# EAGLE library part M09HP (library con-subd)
SUB-D

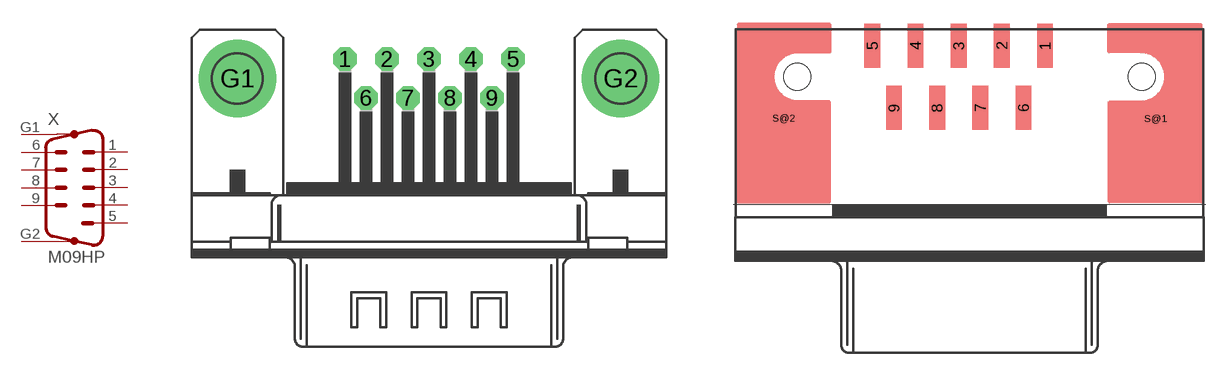
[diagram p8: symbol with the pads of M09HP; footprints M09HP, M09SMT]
Designator prefix X

## M09HP (OC_FARNELL: unknown; OC_NEWARK: unknown)  [M09HP]
1  1  pas
2  2  pas
3  3  pas
4  4  pas
5  5  pas
6  6  pas
7  7  pas
8  8  pas
9  9  pas
G1  G1  pas
G2  G2  pas

## M09HPSMT  [M09SMT]
1  1  pas
2  2  pas
3  3  pas
4  4  pas
5  5  pas
6  6  pas
7  7  pas
8  8  pas
9  9  pas
S@1  G1  pas
S@2  G2  pas

## Footprint M09HP (pad centres in mm)
SUB-D
drill 1.016 octagon: 1 -5.486,1.27; 2 -2.743,1.27; 3 0,1.27; 4 2.743,1.27; 5 5.486,1.27; 6 -4.115,-1.27; 7 -1.372,-1.27; 8 1.372,-1.27; 9 4.115,-1.27
drill 3.302 pad 5.08: G1 -12.522,0; G2 12.522,0

## Footprint M09SMT (pad centres in mm)
D-Sub Steckverbinder Abgewinkelte Messerleisten SMT, Einbauhöhe 3,6mm Source: ERNI-D-Sub-Conmnectors-d.pdf / www.erni.com
smd 1 x 2.8: 1 5.48,1.975; 2 2.74,1.975; 3 0,1.975; 4 -2.74,1.975; 5 -5.48,1.975; 6 4.11,-1.975; 7 1.37,-1.975; 8 -1.37,-1.975; 9 -4.11,-1.975
smd 1 x 1: S@1 12.485,-2.65; S@2 -11.115,-2.625
hole 1.7 at -10.24,0
hole 1.7 at 11.61,0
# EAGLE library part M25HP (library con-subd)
SUB-D

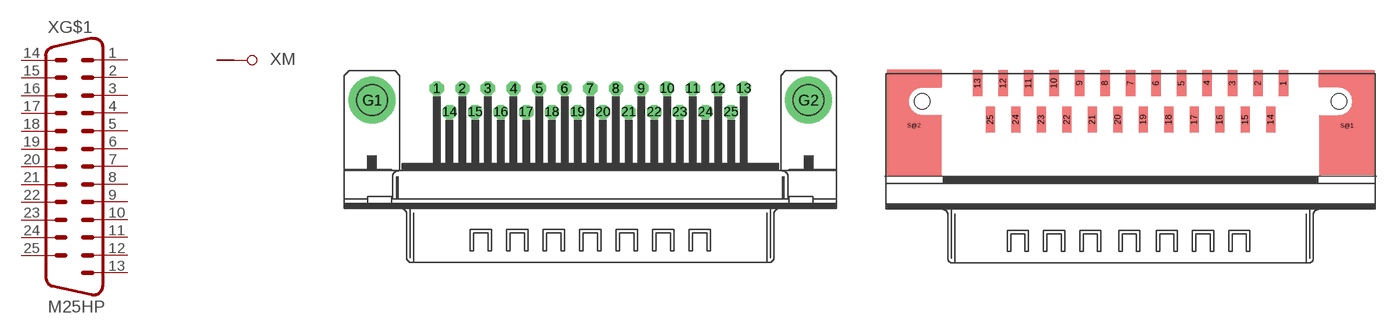
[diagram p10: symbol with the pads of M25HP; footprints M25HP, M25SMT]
Designator prefix X; gates G$1=M25 M=GND

## M25HP (OC_FARNELL: unknown; OC_NEWARK: unknown)  [M25HP]
1  G$1:1  pas
2  G$1:2  pas
3  G$1:3  pas
4  G$1:4  pas
5  G$1:5  pas
6  G$1:6  pas
7  G$1:7  pas
8  G$1:8  pas
9  G$1:9  pas
10  G$1:10  pas
11  G$1:11  pas
12  G$1:12  pas
13  G$1:13  pas
14  G$1:14  pas
15  G$1:15  pas
16  G$1:16  pas
17  G$1:17  pas
18  G$1:18  pas
19  G$1:19  pas
20  G$1:20  pas
21  G$1:21  pas
22  G$1:22  pas
23  G$1:23  pas
24  G$1:24  pas
25  G$1:25  pas
G1  M:G1  pas
G2  M:G2  pas

## M25HPSMT  [M25SMT]
1  G$1:1  pas
2  G$1:2  pas
3  G$1:3  pas
4  G$1:4  pas
5  G$1:5  pas
6  G$1:6  pas
7  G$1:7  pas
8  G$1:8  pas
9  G$1:9  pas
10  G$1:10  pas
11  G$1:11  pas
12  G$1:12  pas
13  G$1:13  pas
14  G$1:14  pas
15  G$1:15  pas
16  G$1:16  pas
17  G$1:17  pas
18  G$1:18  pas
19  G$1:19  pas
20  G$1:20  pas
21  G$1:21  pas
22  G$1:22  pas
23  G$1:23  pas
24  G$1:24  pas
25  G$1:25  pas
S@1  M:G1  pas
S@2  M:G2  pas

## Footprint M25HP (pad centres in mm)
SUB-D
drill 1.016 octagon: 1 -16.561,1.27; 2 -13.792,1.27; 3 -11.049,1.27; 4 -8.28,1.27; 5 -5.512,1.27; 6 -2.769,1.27; 7 0,1.27; 8 2.769,1.27; 9 5.512,1.27; 10 8.28,1.27; 11 11.049,1.27; 12 13.792,1.27; 13 16.561,1.27; 14 -15.189,-1.27; 15 -12.421,-1.27; 16 -9.652,-1.27; 17 -6.909,-1.27; 18 -4.14,-1.27; 19 -1.372,-1.27; 20 1.372,-1.27; 21 4.14,-1.27; 22 6.909,-1.27; 23 9.652,-1.27; 24 12.421,-1.27; 25 15.189,-1.27
drill 3.302 pad 5.08: G1 -23.52,0; G2 23.52,0

## Footprint M25SMT (pad centres in mm)
D-Sub Steckverbinder Abgewinkelte Messerleisten SMT, Einbauhöhe 3,6mm Source: ERNI-D-Sub-Conmnectors-d.pdf / www.erni.com
smd 1 x 2.8: 1 16.56,1.975; 2 13.8,1.975; 3 11.04,1.975; 4 8.28,1.975; 5 5.52,1.975; 6 2.76,1.975; 7 0,1.975; 8 -2.76,1.975; 9 -5.52,1.975; 10 -8.28,1.975; 11 -11.04,1.975; 12 -13.8,1.975; 13 -16.56,1.975; 14 15.18,-1.975; 15 12.42,-1.975; 16 9.66,-1.975; 17 6.9,-1.975; 18 4.14,-1.975; 19 1.38,-1.975; 20 -1.38,-1.975; 21 -4.14,-1.975; 22 -6.9,-1.975; 23 -9.66,-1.975; 24 -12.42,-1.975; 25 -15.18,-1.975
smd 1 x 1: S@1 23.445,-2.65; S@2 -23.445,-2.625
hole 1.7 at -22.57,0
hole 1.7 at 22.57,0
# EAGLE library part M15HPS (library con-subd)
SUB-D

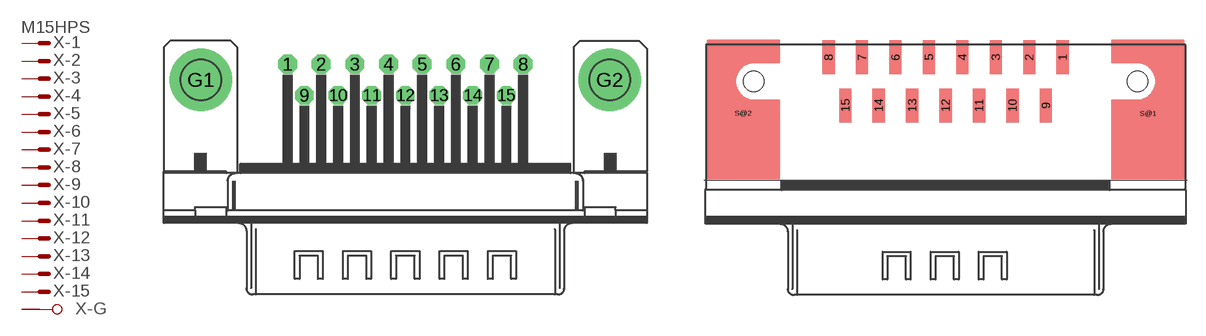
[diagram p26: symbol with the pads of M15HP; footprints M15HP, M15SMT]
Designator prefix X; gates -2=M -3=M -4=M -5=M -6=M -7=M -8=M -9=M -10=M -11=M -12=M -13=M -14=M -15=M -G=GND -1=MV

## M15HPS (OC_FARNELL: unknown; OC_NEWARK: unknown)  [M15HP]
1  -1:M  pas
2  -2:M  pas
3  -3:M  pas
4  -4:M  pas
5  -5:M  pas
6  -6:M  pas
7  -7:M  pas
8  -8:M  pas
9  -9:M  pas
10  -10:M  pas
11  -11:M  pas
12  -12:M  pas
13  -13:M  pas
14  -14:M  pas
15  -15:M  pas
G1  -G:G1  pas
G2  -G:G2  pas

## M15HPSSMT  [M15SMT]
1  -1:M  pas
2  -2:M  pas
3  -3:M  pas
4  -4:M  pas
5  -5:M  pas
6  -6:M  pas
7  -7:M  pas
8  -8:M  pas
9  -9:M  pas
10  -10:M  pas
11  -11:M  pas
12  -12:M  pas
13  -13:M  pas
14  -14:M  pas
15  -15:M  pas
S@1  -G:G1  pas
S@2  -G:G2  pas

## Footprint M15HP (pad centres in mm)
SUB-D
drill 1.016 octagon: 1 -9.601,1.27; 2 -6.858,1.27; 3 -4.115,1.27; 4 -1.372,1.27; 5 1.372,1.27; 6 4.115,1.27; 7 6.858,1.27; 8 9.601,1.27; 9 -8.23,-1.27; 10 -5.486,-1.27; 11 -2.743,-1.27; 12 0,-1.27; 13 2.743,-1.27; 14 5.486,-1.27; 15 8.23,-1.27
drill 3.302 pad 5.08: G1 -16.662,0; G2 16.662,0

## Footprint M15SMT (pad centres in mm)
D-Sub Steckverbinder Abgewinkelte Messerleisten SMT, Einbauhöhe 3,6mm Source: ERNI-D-Sub-Conmnectors-d.pdf / www.erni.com
smd 1 x 2.8: 1 9.59,1.975; 2 6.85,1.975; 3 4.11,1.975; 4 1.37,1.975; 5 -1.37,1.975; 6 -4.11,1.975; 7 -6.85,1.975; 8 -9.59,1.975; 9 8.22,-1.975; 10 5.48,-1.975; 11 2.74,-1.975; 12 0,-1.975; 13 -2.74,-1.975; 14 -5.48,-1.975; 15 -8.22,-1.975
smd 1 x 1: S@1 16.595,-2.65; S@2 -16.595,-2.625
hole 1.7 at -15.72,0
hole 1.7 at 15.72,0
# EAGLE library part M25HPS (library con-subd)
SUB-D

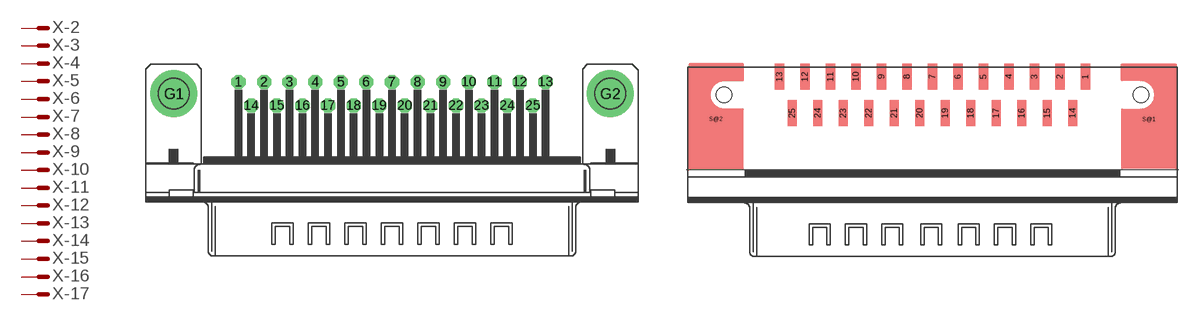
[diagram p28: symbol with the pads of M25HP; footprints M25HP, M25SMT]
Designator prefix X; gates -2=M -3=M -4=M -5=M -6=M -7=M -8=M -9=M -10=M -11=M -12=M -13=M -14=M -15=M -16=M -17=M -18=M -19=M -20=M -21=M -22=M -23=M -24=M -25=M -G=GND -1=MV

## M25HPS (OC_FARNELL: unknown; OC_NEWARK: unknown)  [M25HP]
1  -1:M  pas
2  -2:M  pas
3  -3:M  pas
4  -4:M  pas
5  -5:M  pas
6  -6:M  pas
7  -7:M  pas
8  -8:M  pas
9  -9:M  pas
10  -10:M  pas
11  -11:M  pas
12  -12:M  pas
13  -13:M  pas
14  -14:M  pas
15  -15:M  pas
16  -16:M  pas
17  -17:M  pas
18  -18:M  pas
19  -19:M  pas
20  -20:M  pas
21  -21:M  pas
22  -22:M  pas
23  -23:M  pas
24  -24:M  pas
25  -25:M  pas
G1  -G:G1  pas
G2  -G:G2  pas

## M25HPSSMT  [M25SMT]
1  -1:M  pas
2  -2:M  pas
3  -3:M  pas
4  -4:M  pas
5  -5:M  pas
6  -6:M  pas
7  -7:M  pas
8  -8:M  pas
9  -9:M  pas
10  -10:M  pas
11  -11:M  pas
12  -12:M  pas
13  -13:M  pas
14  -14:M  pas
15  -15:M  pas
16  -16:M  pas
17  -17:M  pas
18  -18:M  pas
19  -19:M  pas
20  -20:M  pas
21  -21:M  pas
22  -22:M  pas
23  -23:M  pas
24  -24:M  pas
25  -25:M  pas
S@1  -G:G1  pas
S@2  -G:G2  pas

## Footprint M25HP (pad centres in mm)
SUB-D
drill 1.016 octagon: 1 -16.561,1.27; 2 -13.792,1.27; 3 -11.049,1.27; 4 -8.28,1.27; 5 -5.512,1.27; 6 -2.769,1.27; 7 0,1.27; 8 2.769,1.27; 9 5.512,1.27; 10 8.28,1.27; 11 11.049,1.27; 12 13.792,1.27; 13 16.561,1.27; 14 -15.189,-1.27; 15 -12.421,-1.27; 16 -9.652,-1.27; 17 -6.909,-1.27; 18 -4.14,-1.27; 19 -1.372,-1.27; 20 1.372,-1.27; 21 4.14,-1.27; 22 6.909,-1.27; 23 9.652,-1.27; 24 12.421,-1.27; 25 15.189,-1.27
drill 3.302 pad 5.08: G1 -23.52,0; G2 23.52,0

## Footprint M25SMT (pad centres in mm)
D-Sub Steckverbinder Abgewinkelte Messerleisten SMT, Einbauhöhe 3,6mm Source: ERNI-D-Sub-Conmnectors-d.pdf / www.erni.com
smd 1 x 2.8: 1 16.56,1.975; 2 13.8,1.975; 3 11.04,1.975; 4 8.28,1.975; 5 5.52,1.975; 6 2.76,1.975; 7 0,1.975; 8 -2.76,1.975; 9 -5.52,1.975; 10 -8.28,1.975; 11 -11.04,1.975; 12 -13.8,1.975; 13 -16.56,1.975; 14 15.18,-1.975; 15 12.42,-1.975; 16 9.66,-1.975; 17 6.9,-1.975; 18 4.14,-1.975; 19 1.38,-1.975; 20 -1.38,-1.975; 21 -4.14,-1.975; 22 -6.9,-1.975; 23 -9.66,-1.975; 24 -12.42,-1.975; 25 -15.18,-1.975
smd 1 x 1: S@1 23.445,-2.65; S@2 -23.445,-2.625
hole 1.7 at -22.57,0
hole 1.7 at 22.57,0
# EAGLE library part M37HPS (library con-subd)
SUB-D

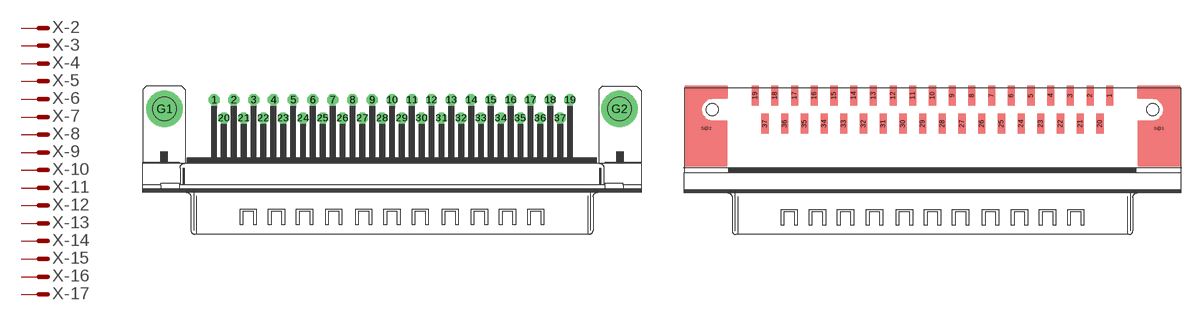
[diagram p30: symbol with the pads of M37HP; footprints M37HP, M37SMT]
Designator prefix X; gates -2=M -3=M -4=M -5=M -6=M -7=M -8=M -9=M -10=M -11=M -12=M -13=M -14=M -15=M -16=M -17=M -18=M -19=M -20=M -21=M -22=M -23=M -24=M -25=M -26=M -27=M -28=M -29=M -30=M -31=M -32=M -33=M -34=M -35=M -36=M -37=M -G=GND -1=MV

## M37HPS (OC_FARNELL: unknown; OC_NEWARK: unknown)  [M37HP]
1  -1:M  pas
2  -2:M  pas
3  -3:M  pas
4  -4:M  pas
5  -5:M  pas
6  -6:M  pas
7  -7:M  pas
8  -8:M  pas
9  -9:M  pas
10  -10:M  pas
11  -11:M  pas
12  -12:M  pas
13  -13:M  pas
14  -14:M  pas
15  -15:M  pas
16  -16:M  pas
17  -17:M  pas
18  -18:M  pas
19  -19:M  pas
20  -20:M  pas
21  -21:M  pas
22  -22:M  pas
23  -23:M  pas
24  -24:M  pas
25  -25:M  pas
26  -26:M  pas
27  -27:M  pas
28  -28:M  pas
29  -29:M  pas
30  -30:M  pas
31  -31:M  pas
32  -32:M  pas
33  -33:M  pas
34  -34:M  pas
35  -35:M  pas
36  -36:M  pas
37  -37:M  pas
G1  -G:G1  pas
G2  -G:G2  pas

## M37HPSSMT  [M37SMT]
1  -1:M  pas
2  -2:M  pas
3  -3:M  pas
4  -4:M  pas
5  -5:M  pas
6  -6:M  pas
7  -7:M  pas
8  -8:M  pas
9  -9:M  pas
10  -10:M  pas
11  -11:M  pas
12  -12:M  pas
13  -13:M  pas
14  -14:M  pas
15  -15:M  pas
16  -16:M  pas
17  -17:M  pas
18  -18:M  pas
19  -19:M  pas
20  -20:M  pas
21  -21:M  pas
22  -22:M  pas
23  -23:M  pas
24  -24:M  pas
25  -25:M  pas
26  -26:M  pas
27  -27:M  pas
28  -28:M  pas
29  -29:M  pas
30  -30:M  pas
31  -31:M  pas
32  -32:M  pas
33  -33:M  pas
34  -34:M  pas
35  -35:M  pas
36  -36:M  pas
37  -37:M  pas
S@1  -G:G1  pas
S@2  -G:G2  pas

## Footprint M37HP (pad centres in mm)
SUB-D
drill 1.016 octagon: 1 -24.841,1.27; 2 -22.098,1.27; 3 -19.329,1.27; 4 -16.561,1.27; 5 -13.818,1.27; 6 -11.049,1.27; 7 -8.28,1.27; 8 -5.512,1.27; 9 -2.769,1.27; 10 0,1.27; 11 2.769,1.27; 12 5.512,1.27; 13 8.28,1.27; 14 11.049,1.27; 15 13.792,1.27; 16 16.561,1.27; 17 19.329,1.27; 18 22.073,1.27; 19 24.841,1.27; 20 -23.47,-1.27; 21 -20.701,-1.27; 22 -17.958,-1.27; 23 -15.189,-1.27; 24 -12.421,-1.27; 25 -9.652,-1.27; 26 -6.909,-1.27; 27 -4.14,-1.27; 28 -1.372,-1.27; 29 1.372,-1.27; 30 4.14,-1.27; 31 6.909,-1.27; 32 9.652,-1.27; 33 12.421,-1.27; 34 15.189,-1.27; 35 17.932,-1.27; 36 20.701,-1.27; 37 23.47,-1.27
drill 3.302 pad 5.08: G1 -31.75,0; G2 31.75,0

## Footprint M37SMT (pad centres in mm)
D-Sub Steckverbinder Abgewinkelte Messerleisten SMT, Einbauhöhe 3,6mm Source: ERNI-D-Sub-Conmnectors-d.pdf / www.erni.com
smd 1 x 2.8: 1 24.84,1.975; 2 22.08,1.975; 3 19.32,1.975; 4 16.56,1.975; 5 13.8,1.975; 6 11.04,1.975; 7 8.28,1.975; 8 5.52,1.975; 9 2.76,1.975; 10 0,1.975; 11 -2.76,1.975; 12 -5.52,1.975; 13 -8.28,1.975; 14 -11.04,1.975; 15 -13.8,1.975; 16 -16.56,1.975; 17 -19.32,1.975; 18 -22.08,1.975; 19 -24.84,1.975; 20 23.46,-1.975; 21 20.7,-1.975; 22 17.94,-1.975; 23 15.18,-1.975; 24 12.42,-1.975; 25 9.66,-1.975; 26 6.9,-1.975; 27 4.14,-1.975; 28 1.38,-1.975; 29 -1.38,-1.975; 30 -4.14,-1.975; 31 -6.9,-1.975; 32 -9.66,-1.975; 33 -12.42,-1.975; 34 -15.18,-1.975; 35 -17.94,-1.975; 36 -20.7,-1.975; 37 -23.46,-1.975
smd 1 x 1: S@1 31.725,-2.65; S@2 -31.725,-2.625
hole 1.7 at -30.85,0
hole 1.7 at 30.85,0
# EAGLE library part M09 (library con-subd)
SUB-D

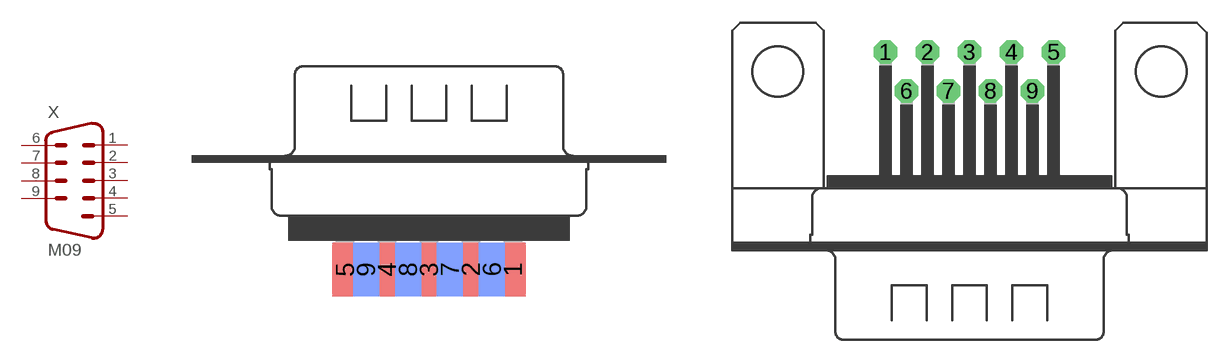
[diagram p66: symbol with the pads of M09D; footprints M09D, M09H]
Designator prefix X

## M09D (OC_FARNELL: unknown; OC_NEWARK: unknown)  [M09D]
1  1  pas
2  2  pas
3  3  pas
4  4  pas
5  5  pas
6  6  pas
7  7  pas
8  8  pas
9  9  pas

## M09H (OC_FARNELL: unknown; OC_NEWARK: unknown)  [M09H]
Pads as for M09D

## M09HP (OC_FARNELL: unknown; OC_NEWARK: unknown)  [M09HP]
Pads as for M09D

## M09V (OC_FARNELL: unknown; OC_NEWARK: unknown)  [M09V]
Pads as for M09D

## M09VP (OC_FARNELL: unknown; OC_NEWARK: unknown)  [M09VP]
Pads as for M09D

## M09VB (OC_FARNELL: unknown; OC_NEWARK: unknown)  [M09VB]
Pads as for M09D

## M09-182 (OC_FARNELL: unknown; OC_NEWARK: unknown)  [182-009-MALE]
Pads as for M09D

## M09SMT  [M09SMT]
Pads as for M09D

## Footprint M09D (pad centres in mm)
SUB-D
smd 1.7 x 3.5: 1 5.486,-6.045; 2 2.743,-6.045; 3 0,-6.045; 4 -2.743,-6.045; 5 -5.486,-6.045
smd 1.7 x 3.5 bottom: 6 4.115,-6.045; 7 1.372,-6.045; 8 -1.372,-6.045; 9 -4.115,-6.045

## Footprint M09H (pad centres in mm)
SUB-D
drill 1.016 octagon: 1 -5.486,1.27; 2 -2.743,1.27; 3 0,1.27; 4 2.743,1.27; 5 5.486,1.27; 6 -4.115,-1.27; 7 -1.372,-1.27; 8 1.372,-1.27; 9 4.115,-1.27
hole 3.302 at 12.522,0
hole 3.302 at -12.522,0

## Footprint M09HP (pad centres in mm)
SUB-D
drill 1.016 octagon: 1 -5.486,1.27; 2 -2.743,1.27; 3 0,1.27; 4 2.743,1.27; 5 5.486,1.27; 6 -4.115,-1.27; 7 -1.372,-1.27; 8 1.372,-1.27; 9 4.115,-1.27
drill 3.302 pad 5.08: G1 -12.522,0; G2 12.522,0

## Footprint M09V (pad centres in mm)
SUB-D
drill 1.016 octagon: 1 -5.486,1.422; 2 -2.743,1.422; 3 0,1.422; 4 2.743,1.422; 5 5.486,1.422; 6 -4.115,-1.422; 7 -1.372,-1.422; 8 1.372,-1.422; 9 4.115,-1.422
hole 3.302 at -12.522,0
hole 3.302 at 12.522,0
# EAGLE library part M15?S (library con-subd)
SUB-D

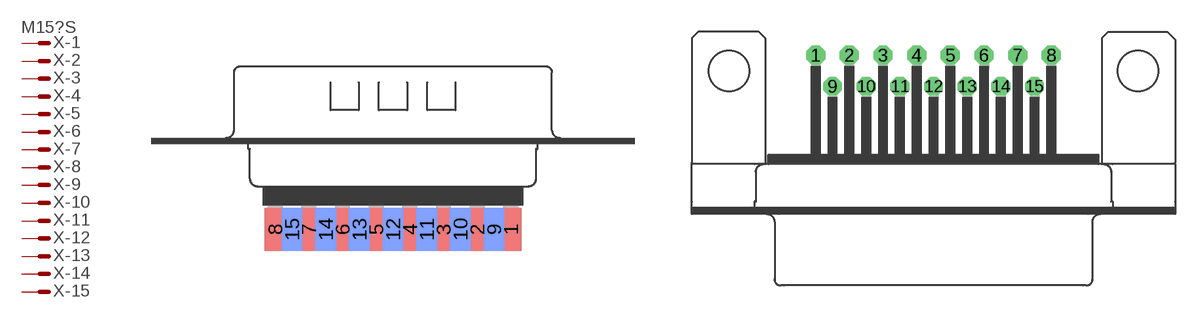
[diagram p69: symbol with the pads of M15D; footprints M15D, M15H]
Designator prefix X; gates -1=MV -2=M -3=M -4=M -5=M -6=M -7=M -8=M -9=M -10=M -11=M -12=M -13=M -14=M -15=M

## M15DS (OC_FARNELL: unknown; OC_NEWARK: unknown)  [M15D]
1  -1:M  pas
2  -2:M  pas
3  -3:M  pas
4  -4:M  pas
5  -5:M  pas
6  -6:M  pas
7  -7:M  pas
8  -8:M  pas
9  -9:M  pas
10  -10:M  pas
11  -11:M  pas
12  -12:M  pas
13  -13:M  pas
14  -14:M  pas
15  -15:M  pas

## M15HS (OC_FARNELL: unknown; OC_NEWARK: unknown)  [M15H]
Pads as for M15D

## M15HPS (OC_FARNELL: unknown; OC_NEWARK: unknown)  [M15HP]
Pads as for M15D

## M15VS (OC_FARNELL: unknown; OC_NEWARK: unknown)  [M15V]
Pads as for M15D

## M15VPS (OC_FARNELL: unknown; OC_NEWARK: unknown)  [M15VP]
Pads as for M15D

## M15VBS (OC_FARNELL: unknown; OC_NEWARK: unknown)  [M15VB]
Pads as for M15D

## M15.590S (OC_FARNELL: unknown; OC_NEWARK: unknown)  [177-015-MALE]
Pads as for M15D

## M15-182S (OC_FARNELL: unknown; OC_NEWARK: unknown)  [182-015-MALE]
Pads as for M15D

## M15SMTS  [M15SMT]
Pads as for M15D

## Footprint M15D (pad centres in mm)
SUB-D
smd 1.7 x 3.5: 1 9.601,-6.045; 2 6.858,-6.045; 3 4.115,-6.045; 4 1.372,-6.045; 5 -1.372,-6.045; 6 -4.115,-6.045; 7 -6.858,-6.045; 8 -9.601,-6.045
smd 1.7 x 3.5 bottom: 9 8.23,-6.045; 10 5.486,-6.045; 11 2.743,-6.045; 12 0,-6.045; 13 -2.743,-6.045; 14 -5.486,-6.045; 15 -8.23,-6.045

## Footprint M15H (pad centres in mm)
SUB-D
drill 1.016 octagon: 1 -9.601,1.27; 2 -6.858,1.27; 3 -4.115,1.27; 4 -1.372,1.27; 5 1.372,1.27; 6 4.115,1.27; 7 6.858,1.27; 8 9.601,1.27; 9 -8.23,-1.27; 10 -5.486,-1.27; 11 -2.743,-1.27; 12 0,-1.27; 13 2.743,-1.27; 14 5.486,-1.27; 15 8.23,-1.27
hole 3.302 at 16.662,0
hole 3.302 at -16.662,0

## Footprint M15HP (pad centres in mm)
SUB-D
drill 1.016 octagon: 1 -9.601,1.27; 2 -6.858,1.27; 3 -4.115,1.27; 4 -1.372,1.27; 5 1.372,1.27; 6 4.115,1.27; 7 6.858,1.27; 8 9.601,1.27; 9 -8.23,-1.27; 10 -5.486,-1.27; 11 -2.743,-1.27; 12 0,-1.27; 13 2.743,-1.27; 14 5.486,-1.27; 15 8.23,-1.27
drill 3.302 pad 5.08: G1 -16.662,0; G2 16.662,0

## Footprint M15V (pad centres in mm)
SUB-D
drill 1.016 octagon: 1 -9.601,1.422; 2 -6.858,1.422; 3 -4.115,1.422; 4 -1.372,1.422; 5 1.372,1.422; 6 4.115,1.422; 7 6.858,1.422; 8 9.601,1.422; 9 -8.23,-1.422; 10 -5.486,-1.422; 11 -2.743,-1.422; 12 0,-1.422; 13 2.743,-1.422; 14 5.486,-1.422; 15 8.23,-1.422
hole 3.302 at 16.662,0
hole 3.302 at -16.662,0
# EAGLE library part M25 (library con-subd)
SUB-D

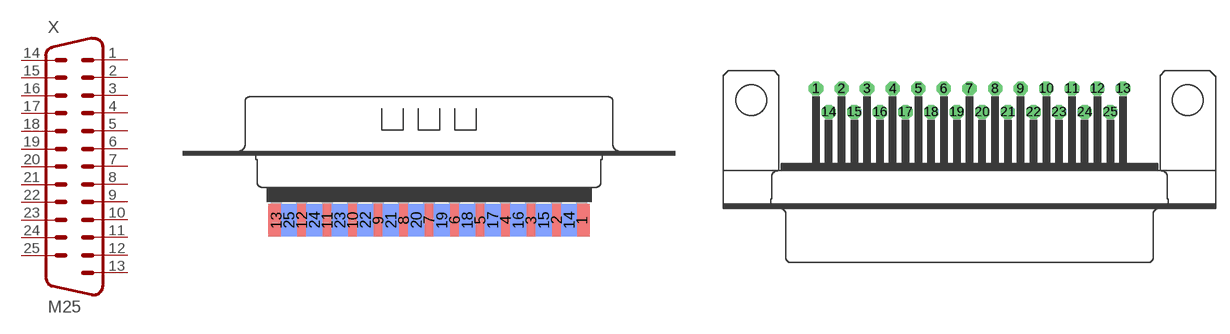
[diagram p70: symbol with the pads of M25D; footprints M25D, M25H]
Designator prefix X

## M25D (OC_FARNELL: unknown; OC_NEWARK: unknown)  [M25D]
1  1  pas
2  2  pas
3  3  pas
4  4  pas
5  5  pas
6  6  pas
7  7  pas
8  8  pas
9  9  pas
10  10  pas
11  11  pas
12  12  pas
13  13  pas
14  14  pas
15  15  pas
16  16  pas
17  17  pas
18  18  pas
19  19  pas
20  20  pas
21  21  pas
22  22  pas
23  23  pas
24  24  pas
25  25  pas

## M25H (OC_FARNELL: unknown; OC_NEWARK: unknown)  [M25H]
Pads as for M25D

## M25HP (OC_FARNELL: unknown; OC_NEWARK: unknown)  [M25HP]
Pads as for M25D

## M25V (OC_FARNELL: unknown; OC_NEWARK: unknown)  [M25V]
Pads as for M25D

## M25VP (OC_FARNELL: unknown; OC_NEWARK: unknown)  [M25VP]
Pads as for M25D

## M25VB (OC_FARNELL: unknown; OC_NEWARK: unknown)  [M25VB]
Pads as for M25D

## M25-182 (OC_FARNELL: unknown; OC_NEWARK: unknown)  [182-025-MALE]
Pads as for M25D

## M25SMT  [M25SMT]
Pads as for M25D

## Footprint M25D (pad centres in mm)
SUB-D
smd 1.7 x 3.5: 1 16.459,-6.045; 2 13.716,-6.045; 3 10.973,-6.045; 4 8.23,-6.045; 5 5.486,-6.045; 6 2.743,-6.045; 7 0,-6.045; 8 -2.743,-6.045; 9 -5.486,-6.045; 10 -8.23,-6.045; 11 -10.973,-6.045; 12 -13.716,-6.045; 13 -16.459,-6.045
smd 1.7 x 3.5 bottom: 14 15.088,-6.045; 15 12.344,-6.045; 16 9.601,-6.045; 17 6.858,-6.045; 18 4.115,-6.045; 19 1.372,-6.045; 20 -1.372,-6.045; 21 -4.115,-6.045; 22 -6.858,-6.045; 23 -9.601,-6.045; 24 -12.344,-6.045; 25 -15.088,-6.045

## Footprint M25H (pad centres in mm)
SUB-D
drill 1.016 octagon: 1 -16.561,1.27; 2 -13.792,1.27; 3 -11.049,1.27; 4 -8.28,1.27; 5 -5.512,1.27; 6 -2.769,1.27; 7 0,1.27; 8 2.769,1.27; 9 5.512,1.27; 10 8.28,1.27; 11 11.049,1.27; 12 13.792,1.27; 13 16.561,1.27; 14 -15.189,-1.27; 15 -12.421,-1.27; 16 -9.652,-1.27; 17 -6.909,-1.27; 18 -4.14,-1.27; 19 -1.372,-1.27; 20 1.372,-1.27; 21 4.14,-1.27; 22 6.909,-1.27; 23 9.652,-1.27; 24 12.421,-1.27; 25 15.189,-1.27
hole 3.302 at 23.52,0
hole 3.302 at -23.52,0

## Footprint M25HP (pad centres in mm)
SUB-D
drill 1.016 octagon: 1 -16.561,1.27; 2 -13.792,1.27; 3 -11.049,1.27; 4 -8.28,1.27; 5 -5.512,1.27; 6 -2.769,1.27; 7 0,1.27; 8 2.769,1.27; 9 5.512,1.27; 10 8.28,1.27; 11 11.049,1.27; 12 13.792,1.27; 13 16.561,1.27; 14 -15.189,-1.27; 15 -12.421,-1.27; 16 -9.652,-1.27; 17 -6.909,-1.27; 18 -4.14,-1.27; 19 -1.372,-1.27; 20 1.372,-1.27; 21 4.14,-1.27; 22 6.909,-1.27; 23 9.652,-1.27; 24 12.421,-1.27; 25 15.189,-1.27
drill 3.302 pad 5.08: G1 -23.52,0; G2 23.52,0

## Footprint M25V (pad centres in mm)
SUB-D
drill 1.016 octagon: 1 -16.561,1.422; 2 -13.792,1.422; 3 -11.049,1.422; 4 -8.28,1.422; 5 -5.512,1.422; 6 -2.769,1.422; 7 0,1.422; 8 2.769,1.422; 9 5.512,1.422; 10 8.28,1.422; 11 11.049,1.422; 12 13.792,1.422; 13 16.561,1.422; 14 -15.189,-1.422; 15 -12.421,-1.422; 16 -9.652,-1.422; 17 -6.909,-1.422; 18 -4.14,-1.422; 19 -1.372,-1.422; 20 1.372,-1.422; 21 4.14,-1.422; 22 6.909,-1.422; 23 9.652,-1.422; 24 12.421,-1.422; 25 15.189,-1.422
hole 3.302 at 23.52,0
hole 3.302 at -23.52,0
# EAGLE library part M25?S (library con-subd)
SUB-D

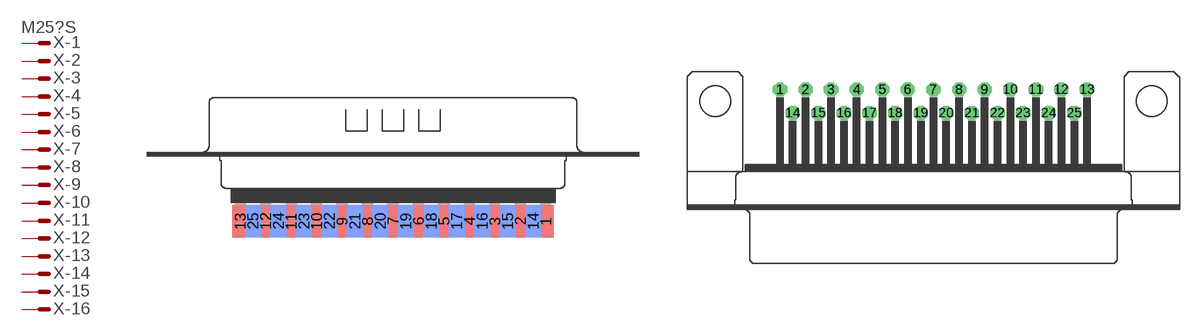
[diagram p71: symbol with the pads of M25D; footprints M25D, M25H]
Designator prefix X; gates -1=MV -2=M -3=M -4=M -5=M -6=M -7=M -8=M -9=M -10=M -11=M -12=M -13=M -14=M -15=M -16=M -17=M -18=M -19=M -20=M -21=M -22=M -23=M -24=M -25=M

## M25DS (OC_FARNELL: unknown; OC_NEWARK: unknown)  [M25D]
1  -1:M  pas
2  -2:M  pas
3  -3:M  pas
4  -4:M  pas
5  -5:M  pas
6  -6:M  pas
7  -7:M  pas
8  -8:M  pas
9  -9:M  pas
10  -10:M  pas
11  -11:M  pas
12  -12:M  pas
13  -13:M  pas
14  -14:M  pas
15  -15:M  pas
16  -16:M  pas
17  -17:M  pas
18  -18:M  pas
19  -19:M  pas
20  -20:M  pas
21  -21:M  pas
22  -22:M  pas
23  -23:M  pas
24  -24:M  pas
25  -25:M  pas

## M25HS (OC_FARNELL: unknown; OC_NEWARK: unknown)  [M25H]
Pads as for M25D

## M25HPS (OC_FARNELL: unknown; OC_NEWARK: unknown)  [M25HP]
Pads as for M25D

## M25VS (OC_FARNELL: unknown; OC_NEWARK: unknown)  [M25V]
Pads as for M25D

## M25VPS (OC_FARNELL: unknown; OC_NEWARK: unknown)  [M25VP]
Pads as for M25D

## M25VBS (OC_FARNELL: unknown; OC_NEWARK: unknown)  [M25VB]
Pads as for M25D

## M25.590S (OC_FARNELL: unknown; OC_NEWARK: unknown)  [177-025-MALE]
Pads as for M25D

## M25-182S (OC_FARNELL: unknown; OC_NEWARK: unknown)  [182-025-MALE]
Pads as for M25D

## M25SMTS  [M25SMT]
Pads as for M25D

## Footprint M25D (pad centres in mm)
SUB-D
smd 1.7 x 3.5: 1 16.459,-6.045; 2 13.716,-6.045; 3 10.973,-6.045; 4 8.23,-6.045; 5 5.486,-6.045; 6 2.743,-6.045; 7 0,-6.045; 8 -2.743,-6.045; 9 -5.486,-6.045; 10 -8.23,-6.045; 11 -10.973,-6.045; 12 -13.716,-6.045; 13 -16.459,-6.045
smd 1.7 x 3.5 bottom: 14 15.088,-6.045; 15 12.344,-6.045; 16 9.601,-6.045; 17 6.858,-6.045; 18 4.115,-6.045; 19 1.372,-6.045; 20 -1.372,-6.045; 21 -4.115,-6.045; 22 -6.858,-6.045; 23 -9.601,-6.045; 24 -12.344,-6.045; 25 -15.088,-6.045

## Footprint M25H (pad centres in mm)
SUB-D
drill 1.016 octagon: 1 -16.561,1.27; 2 -13.792,1.27; 3 -11.049,1.27; 4 -8.28,1.27; 5 -5.512,1.27; 6 -2.769,1.27; 7 0,1.27; 8 2.769,1.27; 9 5.512,1.27; 10 8.28,1.27; 11 11.049,1.27; 12 13.792,1.27; 13 16.561,1.27; 14 -15.189,-1.27; 15 -12.421,-1.27; 16 -9.652,-1.27; 17 -6.909,-1.27; 18 -4.14,-1.27; 19 -1.372,-1.27; 20 1.372,-1.27; 21 4.14,-1.27; 22 6.909,-1.27; 23 9.652,-1.27; 24 12.421,-1.27; 25 15.189,-1.27
hole 3.302 at 23.52,0
hole 3.302 at -23.52,0

## Footprint M25HP (pad centres in mm)
SUB-D
drill 1.016 octagon: 1 -16.561,1.27; 2 -13.792,1.27; 3 -11.049,1.27; 4 -8.28,1.27; 5 -5.512,1.27; 6 -2.769,1.27; 7 0,1.27; 8 2.769,1.27; 9 5.512,1.27; 10 8.28,1.27; 11 11.049,1.27; 12 13.792,1.27; 13 16.561,1.27; 14 -15.189,-1.27; 15 -12.421,-1.27; 16 -9.652,-1.27; 17 -6.909,-1.27; 18 -4.14,-1.27; 19 -1.372,-1.27; 20 1.372,-1.27; 21 4.14,-1.27; 22 6.909,-1.27; 23 9.652,-1.27; 24 12.421,-1.27; 25 15.189,-1.27
drill 3.302 pad 5.08: G1 -23.52,0; G2 23.52,0

## Footprint M25V (pad centres in mm)
SUB-D
drill 1.016 octagon: 1 -16.561,1.422; 2 -13.792,1.422; 3 -11.049,1.422; 4 -8.28,1.422; 5 -5.512,1.422; 6 -2.769,1.422; 7 0,1.422; 8 2.769,1.422; 9 5.512,1.422; 10 8.28,1.422; 11 11.049,1.422; 12 13.792,1.422; 13 16.561,1.422; 14 -15.189,-1.422; 15 -12.421,-1.422; 16 -9.652,-1.422; 17 -6.909,-1.422; 18 -4.14,-1.422; 19 -1.372,-1.422; 20 1.372,-1.422; 21 4.14,-1.422; 22 6.909,-1.422; 23 9.652,-1.422; 24 12.421,-1.422; 25 15.189,-1.422
hole 3.302 at 23.52,0
hole 3.302 at -23.52,0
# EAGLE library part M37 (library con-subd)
SUB-D

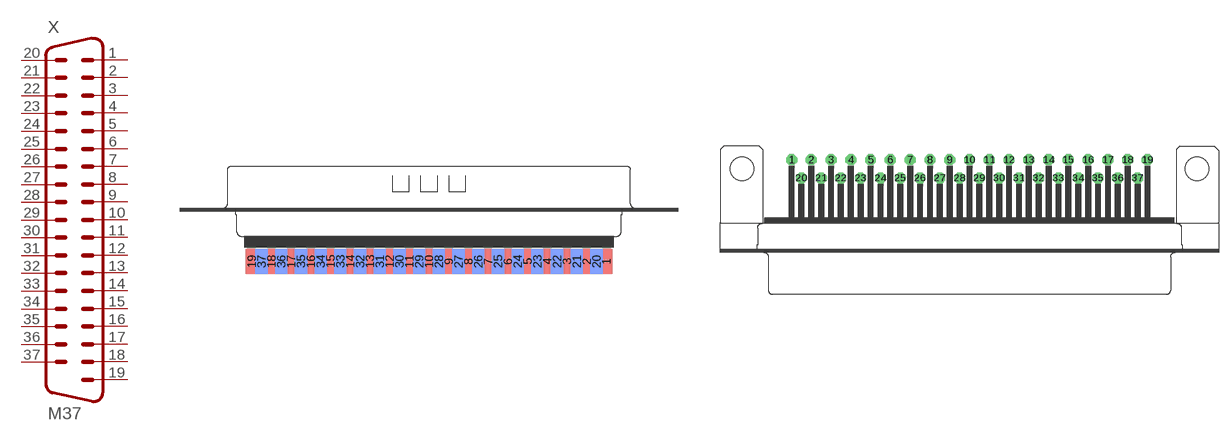
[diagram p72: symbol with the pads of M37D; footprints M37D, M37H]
Designator prefix X

## M37D (OC_FARNELL: unknown; OC_NEWARK: unknown)  [M37D]
1  1  pas
2  2  pas
3  3  pas
4  4  pas
5  5  pas
6  6  pas
7  7  pas
8  8  pas
9  9  pas
10  10  pas
11  11  pas
12  12  pas
13  13  pas
14  14  pas
15  15  pas
16  16  pas
17  17  pas
18  18  pas
19  19  pas
20  20  pas
21  21  pas
22  22  pas
23  23  pas
24  24  pas
25  25  pas
26  26  pas
27  27  pas
28  28  pas
29  29  pas
30  30  pas
31  31  pas
32  32  pas
33  33  pas
34  34  pas
35  35  pas
36  36  pas
37  37  pas

## M37H (OC_FARNELL: unknown; OC_NEWARK: unknown)  [M37H]
Pads as for M37D

## M37HP (OC_FARNELL: unknown; OC_NEWARK: unknown)  [M37HP]
Pads as for M37D

## M37V (OC_FARNELL: unknown; OC_NEWARK: unknown)  [M37V]
Pads as for M37D

## M37VP (OC_FARNELL: unknown; OC_NEWARK: unknown)  [M37VP]
Pads as for M37D

## M37VB (OC_FARNELL: unknown; OC_NEWARK: unknown)  [M37VB]
Pads as for M37D

## M37-182 (OC_FARNELL: unknown; OC_NEWARK: unknown)  [182-037-MALE]
Pads as for M37D

## M37SMT  [M37SMT]
Pads as for M37D

## Footprint M37D (pad centres in mm)
SUB-D
smd 1.7 x 3.5: 1 24.689,-6.045; 2 21.946,-6.045; 3 19.202,-6.045; 4 16.459,-6.045; 5 13.716,-6.045; 6 10.973,-6.045; 7 8.23,-6.045; 8 5.486,-6.045; 9 2.743,-6.045; 10 0,-6.045; 11 -2.743,-6.045; 12 -5.486,-6.045; 13 -8.23,-6.045; 14 -10.973,-6.045; 15 -13.716,-6.045; 16 -16.459,-6.045; 17 -19.202,-6.045; 18 -21.946,-6.045; 19 -24.689,-6.045
smd 1.7 x 3.5 bottom: 20 23.317,-6.045; 21 20.574,-6.045; 22 17.831,-6.045; 23 15.088,-6.045; 24 12.344,-6.045; 25 9.601,-6.045; 26 6.858,-6.045; 27 4.115,-6.045; 28 1.372,-6.045; 29 -1.372,-6.045; 30 -4.115,-6.045; 31 -6.858,-6.045; 32 -9.601,-6.045; 33 -12.344,-6.045; 34 -15.088,-6.045; 35 -17.831,-6.045; 36 -20.574,-6.045; 37 -23.317,-6.045

## Footprint M37H (pad centres in mm)
SUB-D
drill 1.016 octagon: 1 -24.841,1.27; 2 -22.098,1.27; 3 -19.329,1.27; 4 -16.561,1.27; 5 -13.818,1.27; 6 -11.049,1.27; 7 -8.28,1.27; 8 -5.512,1.27; 9 -2.769,1.27; 10 0,1.27; 11 2.769,1.27; 12 5.512,1.27; 13 8.28,1.27; 14 11.049,1.27; 15 13.792,1.27; 16 16.561,1.27; 17 19.329,1.27; 18 22.073,1.27; 19 24.841,1.27; 20 -23.47,-1.27; 21 -20.701,-1.27; 22 -17.958,-1.27; 23 -15.189,-1.27; 24 -12.421,-1.27; 25 -9.652,-1.27; 26 -6.909,-1.27; 27 -4.14,-1.27; 28 -1.372,-1.27; 29 1.372,-1.27; 30 4.14,-1.27; 31 6.909,-1.27; 32 9.652,-1.27; 33 12.421,-1.27; 34 15.189,-1.27; 35 17.932,-1.27; 36 20.701,-1.27; 37 23.47,-1.27
hole 3.302 at 31.75,0
hole 3.302 at -31.75,0

## Footprint M37HP (pad centres in mm)
SUB-D
drill 1.016 octagon: 1 -24.841,1.27; 2 -22.098,1.27; 3 -19.329,1.27; 4 -16.561,1.27; 5 -13.818,1.27; 6 -11.049,1.27; 7 -8.28,1.27; 8 -5.512,1.27; 9 -2.769,1.27; 10 0,1.27; 11 2.769,1.27; 12 5.512,1.27; 13 8.28,1.27; 14 11.049,1.27; 15 13.792,1.27; 16 16.561,1.27; 17 19.329,1.27; 18 22.073,1.27; 19 24.841,1.27; 20 -23.47,-1.27; 21 -20.701,-1.27; 22 -17.958,-1.27; 23 -15.189,-1.27; 24 -12.421,-1.27; 25 -9.652,-1.27; 26 -6.909,-1.27; 27 -4.14,-1.27; 28 -1.372,-1.27; 29 1.372,-1.27; 30 4.14,-1.27; 31 6.909,-1.27; 32 9.652,-1.27; 33 12.421,-1.27; 34 15.189,-1.27; 35 17.932,-1.27; 36 20.701,-1.27; 37 23.47,-1.27
drill 3.302 pad 5.08: G1 -31.75,0; G2 31.75,0

## Footprint M37V (pad centres in mm)
SUB-D
drill 1.016 octagon: 1 -24.841,1.422; 2 -22.098,1.422; 3 -19.329,1.422; 4 -16.561,1.422; 5 -13.818,1.422; 6 -11.049,1.422; 7 -8.28,1.422; 8 -5.512,1.422; 9 -2.769,1.422; 10 0,1.422; 11 2.769,1.422; 12 5.512,1.422; 13 8.28,1.422; 14 11.049,1.422; 15 13.792,1.422; 16 16.561,1.422; 17 19.329,1.422; 18 22.073,1.422; 19 24.841,1.422; 20 -23.47,-1.422; 21 -20.701,-1.422; 22 -17.958,-1.422; 23 -15.189,-1.422; 24 -12.421,-1.422; 25 -9.652,-1.422; 26 -6.909,-1.422; 27 -4.14,-1.422; 28 -1.372,-1.422; 29 1.372,-1.422; 30 4.14,-1.422; 31 6.909,-1.422; 32 9.652,-1.422; 33 12.421,-1.422; 34 15.189,-1.422; 35 17.932,-1.422; 36 20.701,-1.422; 37 23.47,-1.422
hole 3.302 at 31.75,0
hole 3.302 at -31.75,0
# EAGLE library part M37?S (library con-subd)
SUB-D

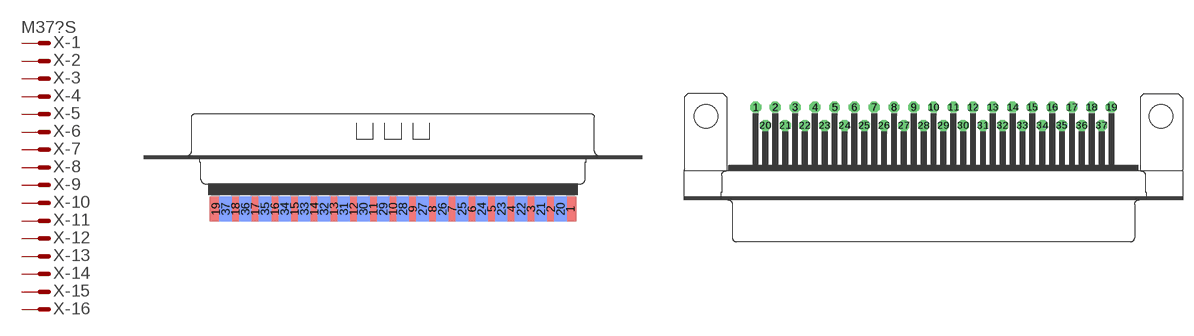
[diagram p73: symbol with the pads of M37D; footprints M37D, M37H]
Designator prefix X; gates -1=MV -2=M -3=M -4=M -5=M -6=M -7=M -8=M -9=M -10=M -11=M -12=M -13=M -14=M -15=M -16=M -17=M -18=M -19=M -20=M -21=M -22=M -23=M -24=M -25=M -26=M -27=M -28=M -29=M -30=M -31=M -32=M -33=M -34=M -35=M -36=M -37=M

## M37DS (OC_FARNELL: unknown; OC_NEWARK: unknown)  [M37D]
1  -1:M  pas
2  -2:M  pas
3  -3:M  pas
4  -4:M  pas
5  -5:M  pas
6  -6:M  pas
7  -7:M  pas
8  -8:M  pas
9  -9:M  pas
10  -10:M  pas
11  -11:M  pas
12  -12:M  pas
13  -13:M  pas
14  -14:M  pas
15  -15:M  pas
16  -16:M  pas
17  -17:M  pas
18  -18:M  pas
19  -19:M  pas
20  -20:M  pas
21  -21:M  pas
22  -22:M  pas
23  -23:M  pas
24  -24:M  pas
25  -25:M  pas
26  -26:M  pas
27  -27:M  pas
28  -28:M  pas
29  -29:M  pas
30  -30:M  pas
31  -31:M  pas
32  -32:M  pas
33  -33:M  pas
34  -34:M  pas
35  -35:M  pas
36  -36:M  pas
37  -37:M  pas

## M37HS (OC_FARNELL: unknown; OC_NEWARK: unknown)  [M37H]
Pads as for M37D

## M37HPS (OC_FARNELL: unknown; OC_NEWARK: unknown)  [M37HP]
Pads as for M37D

## M37VS (OC_FARNELL: unknown; OC_NEWARK: unknown)  [M37V]
Pads as for M37D

## M37VPS (OC_FARNELL: unknown; OC_NEWARK: unknown)  [M37VP]
Pads as for M37D

## M37VBS (OC_FARNELL: unknown; OC_NEWARK: unknown)  [M37VB]
Pads as for M37D

## M37.590S (OC_FARNELL: unknown; OC_NEWARK: unknown)  [177-037-MALE]
Pads as for M37D

## M37-182S (OC_FARNELL: unknown; OC_NEWARK: unknown)  [182-037-MALE]
Pads as for M37D

## M37SMTS  [M37SMT]
Pads as for M37D

## Footprint M37D (pad centres in mm)
SUB-D
smd 1.7 x 3.5: 1 24.689,-6.045; 2 21.946,-6.045; 3 19.202,-6.045; 4 16.459,-6.045; 5 13.716,-6.045; 6 10.973,-6.045; 7 8.23,-6.045; 8 5.486,-6.045; 9 2.743,-6.045; 10 0,-6.045; 11 -2.743,-6.045; 12 -5.486,-6.045; 13 -8.23,-6.045; 14 -10.973,-6.045; 15 -13.716,-6.045; 16 -16.459,-6.045; 17 -19.202,-6.045; 18 -21.946,-6.045; 19 -24.689,-6.045
smd 1.7 x 3.5 bottom: 20 23.317,-6.045; 21 20.574,-6.045; 22 17.831,-6.045; 23 15.088,-6.045; 24 12.344,-6.045; 25 9.601,-6.045; 26 6.858,-6.045; 27 4.115,-6.045; 28 1.372,-6.045; 29 -1.372,-6.045; 30 -4.115,-6.045; 31 -6.858,-6.045; 32 -9.601,-6.045; 33 -12.344,-6.045; 34 -15.088,-6.045; 35 -17.831,-6.045; 36 -20.574,-6.045; 37 -23.317,-6.045

## Footprint M37H (pad centres in mm)
SUB-D
drill 1.016 octagon: 1 -24.841,1.27; 2 -22.098,1.27; 3 -19.329,1.27; 4 -16.561,1.27; 5 -13.818,1.27; 6 -11.049,1.27; 7 -8.28,1.27; 8 -5.512,1.27; 9 -2.769,1.27; 10 0,1.27; 11 2.769,1.27; 12 5.512,1.27; 13 8.28,1.27; 14 11.049,1.27; 15 13.792,1.27; 16 16.561,1.27; 17 19.329,1.27; 18 22.073,1.27; 19 24.841,1.27; 20 -23.47,-1.27; 21 -20.701,-1.27; 22 -17.958,-1.27; 23 -15.189,-1.27; 24 -12.421,-1.27; 25 -9.652,-1.27; 26 -6.909,-1.27; 27 -4.14,-1.27; 28 -1.372,-1.27; 29 1.372,-1.27; 30 4.14,-1.27; 31 6.909,-1.27; 32 9.652,-1.27; 33 12.421,-1.27; 34 15.189,-1.27; 35 17.932,-1.27; 36 20.701,-1.27; 37 23.47,-1.27
hole 3.302 at 31.75,0
hole 3.302 at -31.75,0

## Footprint M37HP (pad centres in mm)
SUB-D
drill 1.016 octagon: 1 -24.841,1.27; 2 -22.098,1.27; 3 -19.329,1.27; 4 -16.561,1.27; 5 -13.818,1.27; 6 -11.049,1.27; 7 -8.28,1.27; 8 -5.512,1.27; 9 -2.769,1.27; 10 0,1.27; 11 2.769,1.27; 12 5.512,1.27; 13 8.28,1.27; 14 11.049,1.27; 15 13.792,1.27; 16 16.561,1.27; 17 19.329,1.27; 18 22.073,1.27; 19 24.841,1.27; 20 -23.47,-1.27; 21 -20.701,-1.27; 22 -17.958,-1.27; 23 -15.189,-1.27; 24 -12.421,-1.27; 25 -9.652,-1.27; 26 -6.909,-1.27; 27 -4.14,-1.27; 28 -1.372,-1.27; 29 1.372,-1.27; 30 4.14,-1.27; 31 6.909,-1.27; 32 9.652,-1.27; 33 12.421,-1.27; 34 15.189,-1.27; 35 17.932,-1.27; 36 20.701,-1.27; 37 23.47,-1.27
drill 3.302 pad 5.08: G1 -31.75,0; G2 31.75,0

## Footprint M37V (pad centres in mm)
SUB-D
drill 1.016 octagon: 1 -24.841,1.422; 2 -22.098,1.422; 3 -19.329,1.422; 4 -16.561,1.422; 5 -13.818,1.422; 6 -11.049,1.422; 7 -8.28,1.422; 8 -5.512,1.422; 9 -2.769,1.422; 10 0,1.422; 11 2.769,1.422; 12 5.512,1.422; 13 8.28,1.422; 14 11.049,1.422; 15 13.792,1.422; 16 16.561,1.422; 17 19.329,1.422; 18 22.073,1.422; 19 24.841,1.422; 20 -23.47,-1.422; 21 -20.701,-1.422; 22 -17.958,-1.422; 23 -15.189,-1.422; 24 -12.421,-1.422; 25 -9.652,-1.422; 26 -6.909,-1.422; 27 -4.14,-1.422; 28 -1.372,-1.422; 29 1.372,-1.422; 30 4.14,-1.422; 31 6.909,-1.422; 32 9.652,-1.422; 33 12.421,-1.422; 34 15.189,-1.422; 35 17.932,-1.422; 36 20.701,-1.422; 37 23.47,-1.422
hole 3.302 at 31.75,0
hole 3.302 at -31.75,0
